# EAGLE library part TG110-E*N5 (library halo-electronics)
E-Ultra (TM) 10/100BASE-TX SOIC-16 Fast Ethernet Magnetic Modules Source: www.haloelectronics.com .. e-ultra.pdf

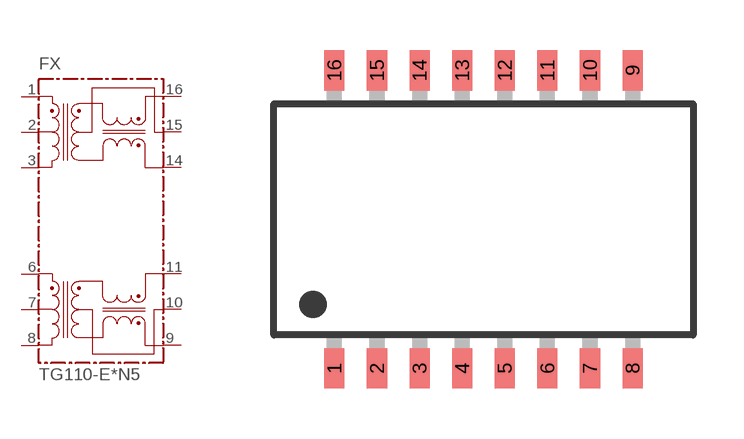
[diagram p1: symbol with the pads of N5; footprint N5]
Designator prefix FX

## TG110-E055N5, TG110-E120N5, TG110-E125N5, TG110-E139N5  [N5]
1  1  pas
2  2  pas
3  3  pas
6  6  pas
7  7  pas
8  8  pas
9  9  pas
10  10  pas
11  11  pas
14  14  pas
15  15  pas
16  16  pas

## Footprint N5 (pad centres in mm)
E-Ultra (TM) 10/100BASE-TX SOIC-16 Fast Ethernet Magnetic Modules Source: www.haloelectronics.com .. e-ultra.pdf
smd 0.6 x 1.2: 1 -4.445,-4.445; 2 -3.175,-4.445; 3 -1.905,-4.445; 4 -0.635,-4.445; 5 0.635,-4.445; 6 1.905,-4.445; 7 3.175,-4.445; 8 4.445,-4.445; 9 4.445,4.445; 10 3.175,4.445; 11 1.905,4.445; 12 0.635,4.445; 13 -0.635,4.445; 14 -1.905,4.445; 15 -3.175,4.445; 16 -4.445,4.445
